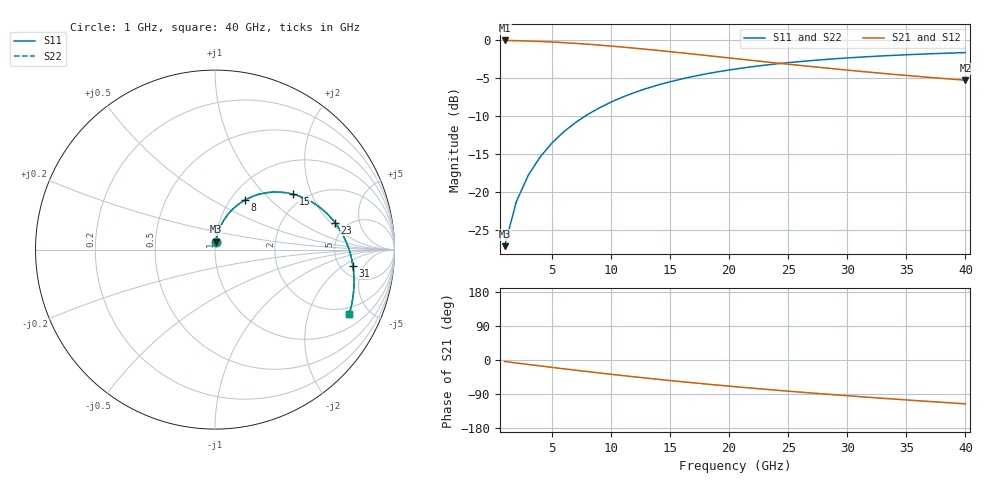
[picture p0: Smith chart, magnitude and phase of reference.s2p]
! circuitRF F0 spike reference -- case A, Palace, round wire, after 2 AMR iterations (final mesh, 987k ND unknowns)
! Palace postpro/port-S.csv, dB/deg -> RI; port 1 excited only; S22 = S11 and S12 = S21 by the mirror symmetry of the geometry about x = 0
# GHz S RI R 50
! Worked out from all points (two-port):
!   40 points, 1 GHz to 40 GHz, reference 50 ohm
!   highest |S21| = -0.02 dB at 1 GHz (marker M1); lowest = -5.3 dB at 40 GHz (marker M2)
!   |S21| within 3 dB of the highest: start of sweep to 24.18 GHz
!   lowest |S11| = -27.2 dB at 1 GHz (marker M3), VSWR 1.09, Z = 50.2 + j4.39 ohm
!   |S11| at or under -10 dB: start of sweep to 7.826 GHz
!   |S22| runs from -27.2 to -1.6 dB; largest |S21 - S12| = 0
!   S11 on the Smith chart (normalised r, x): 1 GHz: 1.00, +0.09; 8 GHz: 1.16, +0.72; 15 GHz: 1.72, +1.49; 23 GHz: 3.99, +2.27; 31 GHz: 6.52, -2.90; 40 GHz: 1.61, -3.72
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1  0.00437 0.0436  0.9953 -0.0691  0.9953 -0.0691  0.00437 0.0436
2  0.0137 0.0854  0.9849 -0.1364  0.9849 -0.1364  0.0137 0.0854
3  0.0284 0.1253  0.9686 -0.2018  0.9686 -0.2018  0.0284 0.1253
4  0.0481 0.1627  0.9465 -0.2646  0.9465 -0.2646  0.0481 0.1627
5  0.0724 0.1969  0.9192 -0.3243  0.9192 -0.3243  0.0724 0.1969
6  0.1007 0.2276  0.8873 -0.3801  0.8873 -0.3801  0.1007 0.2276
7  0.1324 0.2541  0.8513 -0.4319  0.8513 -0.4319  0.1324 0.2541
8  0.1669 0.2764  0.8119 -0.4792  0.8119 -0.4792  0.1669 0.2764
9  0.2034 0.2942  0.7697 -0.5218  0.7697 -0.5218  0.2034 0.2942
11  0.2802 0.3161  0.6798 -0.5931  0.6798 -0.5931  0.2802 0.3161
12  0.3193 0.3204  0.6331 -0.6218  0.6331 -0.6218  0.3193 0.3204
14  0.3965 0.3167  0.539 -0.6662  0.539 -0.6662  0.3965 0.3167
15  0.4338 0.3091  0.4923 -0.6824  0.4923 -0.6824  0.4338 0.3091
18  0.5365 0.2671  0.3578 -0.7101  0.3578 -0.7101  0.5365 0.2671
21  0.6219 0.2026  0.2352 -0.7127  0.2352 -0.7127  0.6219 0.2026
23  0.6681 0.1508  0.1613 -0.704  0.1613 -0.704  0.6681 0.1508
25  0.7055 0.0943  0.094 -0.6892  0.094 -0.6892  0.7055 0.0943
27  0.7344 0.0345  0.0331 -0.6696  0.0331 -0.6696  0.7344 0.0345
31  0.7683 -0.0893  -0.0712 -0.6211  -0.0712 -0.6211  0.7683 -0.0893
34  0.7749 -0.1824  -0.1357 -0.5797  -0.1357 -0.5797  0.7749 -0.1824
37  0.7674 -0.2731  -0.1903 -0.5362  -0.1903 -0.5362  0.7674 -0.2731
40  0.7475 -0.3598  -0.2365 -0.4919  -0.2365 -0.4919  0.7475 -0.3598
